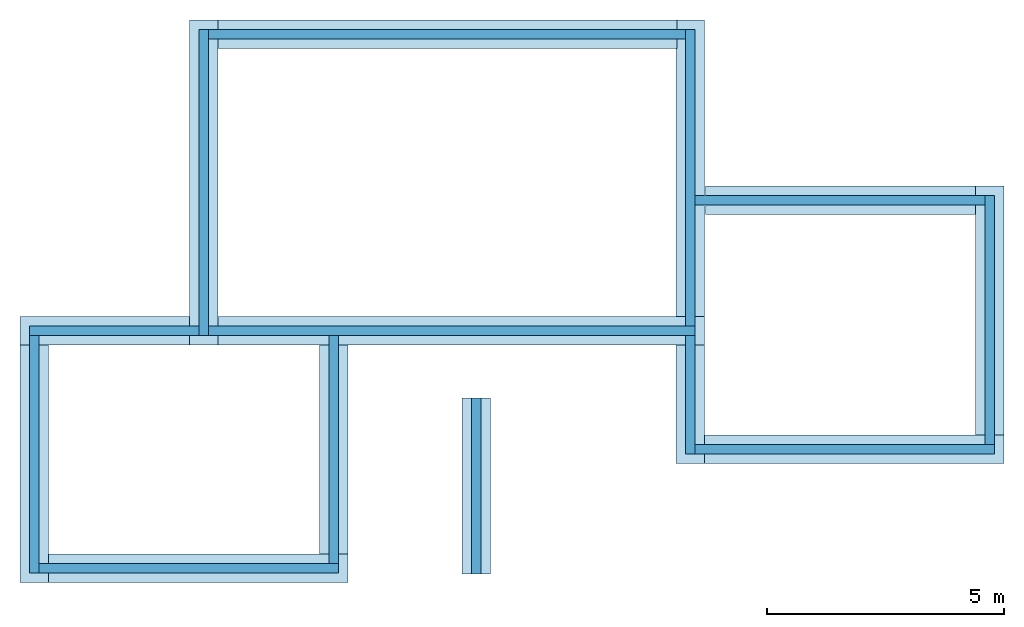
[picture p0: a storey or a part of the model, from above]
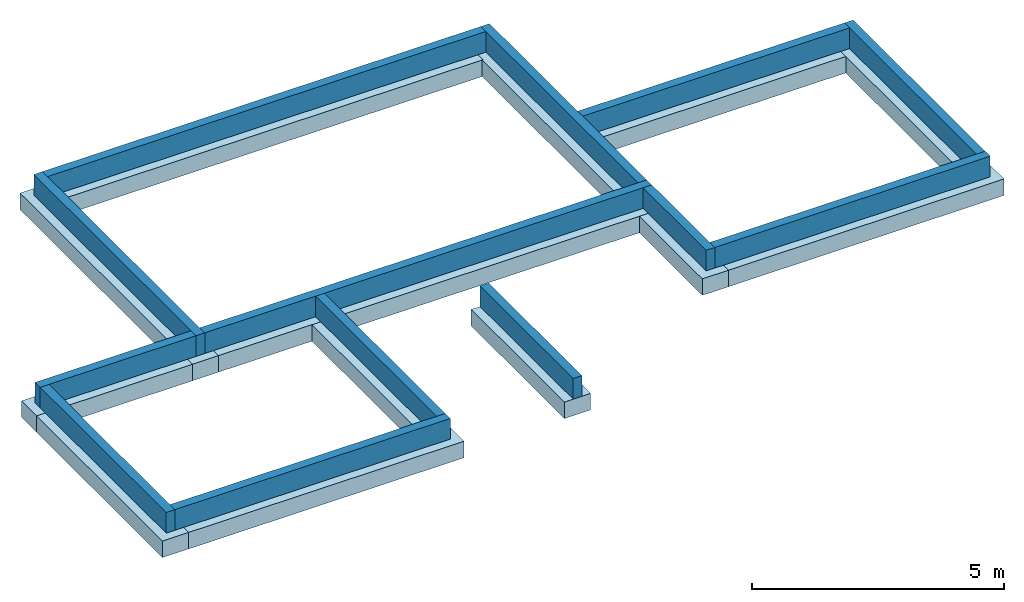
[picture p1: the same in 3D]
Properties of the parts of a building model (IFC4)

# File
Description: no view
File name: C:\Users\benjamin.carre\OneDrive - BTPCFA NOUVELLE-AQUITAINE\Bureau\Data.B²\Armoire BIM\Bim3D\Maquette B²\ALL21 EDC7.2.ifc
Time: 2022-07-11T13:41:35
Author: CARRE Benjamin
Organization: Nemetschek AG, Konrad-Zuse-Platz 1, 81829 Munich / Germany
Written by: EDMsix Version 2.0100.09 Sep 7 2016
Made in: Allplan 2021.1 08.04.2021 - 15:31:04

# IfcBuildingStorey (5)
In: Projet de Construction
Name | Elevation (m)
Environnement | -1.15
Fondations | -1.15
Plancher Bas | -0.25
RDC | -0.05
R+1 | 2.8

# IfcSpace (14)
AllplanAttributes - Pourtour de la salle: R; Type_surface_277: N; Type_surface_surf_habitable: WO; Règl_constr_ajout_SB: 0; Type_d'utilisation_Din277: SU; Règl_constr_ajout_SHOE: 0; Pièce_ss_escalier_(Surf_hab_2m_min.): 0; Facteur_surf_habitable_pièce: 1; Facteur_DIN277: 1; Unité: m²; Nom_de_macro: Pièce
Name | In | Id_élt_Allmétré
Cellier | RDC | 0062Pce0000000003
Buanderie | RDC | 0062Pce0000000010
Cuisine | RDC | 0062Pce0000000017
Salle à Manger | RDC | 0062Pce0000000024
Salon | RDC | 0062Pce0000000031
WC | RDC | 0062Pce0000000038
Bureau | RDC | 0062Pce0000000045
Salle de Jeux | RDC | 0062Pce0000000052
Sas | RDC | 0062Pce0000000059
CH1 | R+1 | 0058Pce0000000003
Petit Salon | R+1 | 0058Pce0000000031
SDB | R+1 | 0058Pce0000000024
CH2 | R+1 | 0058Pce0000000010
CH3 | R+1 | 0058Pce0000000017

# IfcBeam (7)
In: R+1
AllplanAttributes - Métier: Charpenterie, ouvrages en bois; Unité: m³; Nom_de_macro: Sous-poutre
Pset_BeamCommon - Status: Nouvelle construction
Name | Id_élt_Allmétré
 | 0055S-p0000000019
 | 0055S-p0000000100
 | 0055S-p0000000111
 | 0055S-p0000000130
 | 0055S-p0000000137
 | 0055S-p0000000052
 | 0055S-p0000000096

# IfcBuildingElementProxy (5)
In: Environnement
AllplanAttributes - BI: 3000; BS: 0; V6: 0; V7: 0; V8: 0; V9: 0; Unité: Qt; Nom_de_macro: Macro
Name | Désignation | Id_élt_Allmétré
Banc | Banc | 0012MaU0000000058
Parasol rond | Parasol rond | 0012MaU0000000054
Parasol rond | Parasol rond | 0012MaU0000000061
Femme debout 2, blanche | Femme debout 2, blanche | 0012MaU0000000049
Banc | Banc | 0012MaU0000000069

# IfcChimney (3)
PredefinedType: USERDEFINED
AllplanAttributes - Rayon_tirage: 200; Unité: m; Nom_de_macro: Cheminée
Pset_ChimneyCommon - Status: Nouvelle construction
Name | In | Id_élt_Allmétré
 | RDC | 0045Che0000000002
 | RDC | 0045Che0000000007
 | R+1 | 0056Che0000000002

# IfcColumn (4)
In: RDC
PredefinedType: COLUMN
AllplanAttributes - Unité: m; Nom_de_macro: Poteau
Pset_ColumnCommon - Status: Nouvelle construction
Name | Id_élt_Allmétré
 | 0046Pot0000000415
 | 0046Pot0000000422
 | 0046Pot0000000423
 | 0046Pot0000000424

# IfcDoor: 1 vantail blanc 1 partie latéral
In: RDC
Type - PredefinedType: DOOR; ParameterTakesPrecedence: no
OverallHeight: 2.15 m; OverallWidth: 1.3 m
AllplanAttributes (1 vantail blanc 1 partie latéral) - V6: 0; V7: 0; V8: 0; V9: 0; Version: 3.0; Désignation: 1 vantail blanc 1 partie latérale; Plugin_désignation: MainObject; Plugin_nom_objet: SmartPartCompressed; Prendre en compte la part de vitrage: 0; Version_SMT: 6.0; Id_élt_Allmétré: 0040MaU0000002760; Unité: Qt; Nom_de_macro: Macro de porte, SmartPart
AllplanQuantities - GlassSurface: 0.5025; HeightWindowSillOutside: 0; HeightWindowSillInside: 0; OffsetOpeningBottom: 0; OffsetOpeningTop: 0; OffsetOpeningLeft: 0; OffsetOpeningRight: 0; DeductionOpeningBottom: 0; DeductionOpeningLeft: 70; DeductionOpeningRight: 70; DeductionOpeningTop: 70

# IfcDoor: 1 vantail encadrement, blanc
In: RDC
Type - PredefinedType: DOOR; OperationType: SINGLE_SWING_RIGHT; ParameterTakesPrecedence: no
Type - IfcDoorLiningProperties - LiningDepth: 0.07 m; LiningThickness: 0.07 m; LiningOffset: 0 m; LiningToPanelOffsetX: 0 m; LiningToPanelOffsetY: 0 m
OverallHeight: 2.15 m; OverallWidth: 0.9 m
AllplanAttributes (1 vantail encadrement, blanc) - V6: 0; V7: 0; V8: 0; V9: 0; Version: 3.0; Désignation: 1 vantail encadrement, blanc; Plugin_désignation: MainObject; Plugin_nom_objet: SmartPartCompressed; Prendre en compte la part de vitrage: 0; Version_SMT: 6.0; Id_élt_Allmétré: 0040MaU0000002792; Unité: Qt; Nom_de_macro: Macro de porte, SmartPart
AllplanQuantities - GlassSurface: 0; HeightWindowSillOutside: 0; HeightWindowSillInside: 0; OffsetOpeningBottom: 0; OffsetOpeningTop: 0; OffsetOpeningLeft: 0; OffsetOpeningRight: 0; DeductionOpeningBottom: 0; DeductionOpeningLeft: 70; DeductionOpeningRight: 70; DeductionOpeningTop: 70

# IfcDoor: 1 vantail sol fini, en bois (11)
Type - PredefinedType: DOOR; OperationType: SINGLE_SWING_RIGHT; ParameterTakesPrecedence: no
Type - IfcDoorLiningProperties - LiningDepth: 0.07 m; LiningThickness: 0.07 m; LiningOffset: 0 m; LiningToPanelOffsetX: 0 m; LiningToPanelOffsetY: 0 m
OverallHeight: 2.04 m; OverallWidth: 0.83 m
AllplanAttributes (1 vantail sol fini, en bois) - V6: 0; V7: 0; V8: 0; V9: 0; Version: 3.0; Désignation: 1 vantail sol fini, en bois; Plugin_désignation: MainObject; Plugin_nom_objet: SmartPartCompressed; Prendre en compte la part de vitrage: 0; Version_SMT: 6.0; Unité: Qt; Nom_de_macro: Macro de porte, SmartPart
AllplanQuantities - GlassSurface: 0; HeightWindowSillOutside: 0; HeightWindowSillInside: 0; OffsetOpeningBottom: 0; OffsetOpeningTop: 0; OffsetOpeningLeft: 0; OffsetOpeningRight: 0; DeductionOpeningBottom: 0; DeductionOpeningLeft: 70; DeductionOpeningRight: 70; DeductionOpeningTop: 70
Name | In | Id_élt_Allmétré
1 vantail sol fini, en bois | RDC | 0042MaU0000000401
1 vantail sol fini, en bois | RDC | 0042MaU0000000398
1 vantail sol fini, en bois | RDC | 0042MaU0000000395
1 vantail sol fini, en bois | RDC | 0042MaU0000000430
1 vantail sol fini, en bois | RDC | 0042MaU0000000433
1 vantail sol fini, en bois | RDC | 0042MaU0000000462
1 vantail sol fini, en bois | RDC | 0042MaU0000000196
1 vantail sol fini, en bois | R+1 | 0052MaU0000000496
1 vantail sol fini, en bois | R+1 | 0052MaU0000000795
1 vantail sol fini, en bois | R+1 | 0052MaU0000000901
1 vantail sol fini, en bois | R+1 | 0052MaU0000000861

# IfcDoor: 3 vantaux blanc, monté (5)
Type - PredefinedType: DOOR; ParameterTakesPrecedence: no
OverallHeight: 2.15 m; OverallWidth: 1.4 m
AllplanAttributes (3 vantaux blanc, monté) - V6: 0; V7: 0; V8: 0; V9: 0; Version: 3.0; Désignation: 3 vantaux blanc, monté; Plugin_désignation: MainObject; Plugin_nom_objet: SmartPartCompressed; Prendre en compte la part de vitrage: 100; Version_SMT: 6.0; Unité: Qt
AllplanQuantities - GlassSurface: 2.14305; HeightWindowSillOutside: 0.03; HeightWindowSillInside: 0.03; OffsetOpeningBottom: 0; OffsetOpeningTop: 0; OffsetOpeningLeft: 0; OffsetOpeningRight: 0; DeductionOpeningBottom: 70; DeductionOpeningLeft: 70; DeductionOpeningRight: 70; DeductionOpeningTop: 70
Name | In | Nom_de_macro | Id_élt_Allmétré
3 vantaux blanc, monté | RDC | Macro de fenêtre, SmartPart | 0040MaU0000003242
3 vantaux blanc, monté | RDC | Macro de fenêtre, SmartPart | 0040MaU0000003331
3 vantaux blanc, monté | RDC | Macro de fenêtre, SmartPart | 0040MaU0000003328
3 vantaux blanc, monté | R+1 | Macro de porte, SmartPart | 0050MaU0000000898
3 vantaux blanc, monté | R+1 | Macro de porte, SmartPart | 0050MaU0000000895

# IfcDoor: 3 vantaux volet roulant, blanc
In: RDC
Type - PredefinedType: DOOR; ParameterTakesPrecedence: no
OverallHeight: 2.15 m; OverallWidth: 2.4 m
AllplanAttributes (3 vantaux volet roulant, blanc) - V6: 0; V7: 0; V8: 0; V9: 0; Version: 3.0; Désignation: 3 vantaux volet roulant, blanc; Plugin_désignation: MainObject; Plugin_nom_objet: SmartPartCompressed; Prendre en compte la part de vitrage: 100; Version_SMT: 6.0; Id_élt_Allmétré: 0040MaU0000003632; Unité: Qt; Nom_de_macro: Macro de porte, SmartPart
AllplanQuantities - GlassSurface: 3.70073; HeightWindowSillOutside: 0.03; HeightWindowSillInside: 0.03; OffsetOpeningBottom: 0; OffsetOpeningTop: 0; OffsetOpeningLeft: 0; OffsetOpeningRight: 0; DeductionOpeningBottom: 70; DeductionOpeningLeft: 70; DeductionOpeningRight: 70; DeductionOpeningTop: 150

# IfcFooting (13)
In: Fondations
PredefinedType: STRIP_FOOTING
AllplanAttributes - Métier: Maçonnerie; Unité: m³; Nom_de_macro: Semelle filante
Pset_FootingCommon - Status: Nouvelle construction
Name | Id_élt_Allmétré
 | 0020SeF0000000046
 | 0020SeF0000000067
 | 0020SeF0000000055
 | 0020SeF0000000129
 | 0020SeF0000000117
 | 0020SeF0000000105
 | 0020SeF0000000028
 | 0020SeF0000000006
 | 0020SeF0000000016
 | 0020SeF0000000096
 | 0020SeF0000000079
 | 0020SeF0000000002
 | 0020SeF0000000179

# IfcFurniture (32)
AllplanAttributes - V6: 0; V7: 0; V8: 0; V9: 0; Nom_de_macro: Meubles
Name | In | BI | BS | Unité | Désignation | Id_élt_Allmétré
Fauteuil C | Environnement | 3100 | 0 | Pcs | Fauteuil C | 0011Meu0000000032
Sofa G | Environnement | 0 | 0 | Pcs | Sofa G | 0011Meu0000000038
Table basse A 100x50x42 | Environnement | 0 | 0 | Pcs | Table basse A 100x50x42 | 0011Meu0000000044
TV 48 pouces | Environnement | 0 | 0 | Qt | TV 48 pouces | 0011Meu0000000049
Fauteuil I | Environnement | 0 | 0 | Pcs | Fauteuil I | 0011Meu0000000056
Table C 180x90x75 | Environnement | 0 | 0 | Pcs | Table C 180x90x75 | 0011Meu0000000061
Chaise G | Environnement | 0 | 0 | Pcs | Chaise G | 0011Meu0000000070
Chaise G | Environnement | 0 | 0 | Pcs | Chaise G | 0011Meu0000000075
Chaise G | Environnement | 0 | 0 | Pcs | Chaise G | 0011Meu0000000077
Chaise G | Environnement | 0 | 0 | Pcs | Chaise G | 0011Meu0000000079
Elément 4 | Environnement | 0 | 0 | Pcs | Elément 4 | 0011Meu0000000097
Elément 7 évier | Environnement | 0 | 0 | Pcs | Elément 7 évier | 0011Meu0000000089
Elément 8 | Environnement | 0 | 0 | Qt | Elément 8 | 0011Meu0000000109
Elément 5 cuisinière | Environnement | 0 | 0 | Pcs | Elément 5 cuisinière | 0011Meu0000000115
Elément 8 | Environnement | 0 | 0 | Qt | Elément 8 | 0011Meu0000000128
Elément 2 four | Environnement | 0 | 0 | Qt | Elément 2 four | 0011Meu0000000122
Table B 130x70 | Environnement | 0 | 0 | Pcs | Table B 130x70 | 0011Meu0000000148
Chaise de bureau E | Environnement | 0 | 0 | Qt | Chaise de bureau E | 0011Meu0000000152
Etagère B 214x46x100 | Environnement | 0 | 0 | Qt | Etagère B 214x46x100 | 0011Meu0000000158
Sofa G | Environnement | 0 | 0 | Pcs | Sofa G | 0011Meu0000000173
TV 48 pouces | Environnement | 0 | 0 | Qt | TV 48 pouces | 0011Meu0000000175
Lit A 90x200 | Environnement | 3100 | 0 | Pcs | Lit A 90x200 | 0012Meu0000000002
Table de nuit A | Environnement | 3100 | 0 | Pcs | Table de nuit A | 0012Meu0000000010
Lit A 90x200 | Environnement | 3100 | 0 | Pcs | Lit A 90x200 | 0012Meu0000000015
Table de nuit A | Environnement | 3100 | 0 | Pcs | Table de nuit A | 0012Meu0000000021
Lit B 140x200 | Environnement | 3100 | 0 | Pcs | Lit B 140x200 | 0012Meu0000000028
Table de nuit A | Environnement | 3100 | 0 | Pcs | Table de nuit A | 0012Meu0000000029
Table de nuit A | Environnement | 3100 | 0 | Pcs | Table de nuit A | 0012Meu0000000039
WC, debout, avec réservoir | RDC | 0 | 50 | Qt | WC, debout, avec réservoir | 0060Meu0000000003
Lavabo 36,5 | RDC | 800 | 0 | Qt | Lavabo 36,5 | 0060Meu0000000012
Douche 100 x 100 | R+1 | 3100 | 0 | Qt | Douche 100 x 100 | 0057Meu0000000004
Lavabo double 120 | R+1 | 3900 | 999199999200000 | Qt | Lavabo double 120 | 0057Meu0000000010

# IfcOpeningStandardCase (40)
PredefinedType: OPENING
AllplanAttributes - Object Layer Attributes #1, Unité: m²
Pset_OpeningElementCommon - Status: Nouvelle construction
Name | In | Object Layer Attributes #1, Métier | Object Layer Attributes #1, Mode_d'ouverture_porte | Object Layer Attributes #1, Id_élt_Allmétré | Object Layer Attributes #1, Nom_de_macro | Object Layer Attributes #2, Catégorie de transformation = Object Layer Attributes #3, Catégorie de transformation | Object Layer Attributes #2, Métier | Object Layer Attributes #2, Id_élt_Allmétré | Object Layer Attributes #2, Unité = Object Layer Attributes #3, Unité | Object Layer Attributes #2, Nom_de_macro = Object Layer Attributes #3, Nom_de_macro | Object Layer Attributes #3, Métier | Object Layer Attributes #3, Id_élt_Allmétré
Baie de porte | RDC | Systèmes d'isolation thermique | - | 0040Por0000002178 | Baie de porte | Nouvelle construction | Maçonnerie | 0040Por0000002177 | m² | Baie de porte | Peintures | 0040Por0000002176 | AllplanAttributes - Object Layer Attributes #2, Mode_d'ouverture_porte: -; Object Layer Attributes #3, Mode_d'ouverture_porte: -
Baie de fenêtre | RDC | Systèmes d'isolation thermique |  | 0040Fen0000002530 | Baie de fenêtre | Nouvelle construction | Maçonnerie | 0040Fen0000002529 | m² | Baie de fenêtre | Peintures | 0040Fen0000002528
Baie de fenêtre | RDC | Systèmes d'isolation thermique |  | 0040Fen0000002684 | Baie de fenêtre | Nouvelle construction | Maçonnerie | 0040Fen0000002683 | m² | Baie de fenêtre | Peintures | 0040Fen0000002682
Baie de fenêtre | RDC | Systèmes d'isolation thermique |  | 0040Fen0000002664 | Baie de fenêtre | Nouvelle construction | Maçonnerie | 0040Fen0000002663 | m² | Baie de fenêtre | Peintures | 0040Fen0000002662
Baie de fenêtre | RDC | Systèmes d'isolation thermique |  | 0040Fen0000002704 | Baie de fenêtre | Nouvelle construction | Maçonnerie | 0040Fen0000002703 | m² | Baie de fenêtre | Peintures | 0040Fen0000002702
Baie de fenêtre | RDC | Systèmes d'isolation thermique |  | 0040Fen0000002644 | Baie de fenêtre | Nouvelle construction | Maçonnerie | 0040Fen0000002643 | m² | Baie de fenêtre | Peintures | 0040Fen0000002642
Baie de porte | RDC | Systèmes d'isolation thermique | - | 0040Por0000002152 | Baie de porte | Nouvelle construction | Maçonnerie | 0040Por0000002151 | m² | Baie de porte | Peintures | 0040Por0000002150 | AllplanAttributes - Object Layer Attributes #2, Mode_d'ouverture_porte: -; Object Layer Attributes #3, Mode_d'ouverture_porte: -
Baie de porte | RDC | Systèmes d'isolation thermique | DIN R | 0040Por0000002384 | Baie de porte | Nouvelle construction | Maçonnerie | 0040Por0000002383 | m² | Baie de porte | Peintures | 0040Por0000002382 | AllplanAttributes - Object Layer Attributes #2, Mode_d'ouverture_porte: DIN R; Object Layer Attributes #3, Mode_d'ouverture_porte: DIN R
Baie de porte | RDC | Systèmes d'isolation thermique | - | 0040Por0000002080 | Baie de porte | Nouvelle construction | Maçonnerie | 0040Por0000002081 | m² | Baie de porte | Peintures | 0040Por0000002082 | AllplanAttributes - Object Layer Attributes #2, Mode_d'ouverture_porte: -; Object Layer Attributes #3, Mode_d'ouverture_porte: -
Baie de porte | RDC | Systèmes d'isolation thermique | - | 0040Por0000002110 | Baie de porte | Nouvelle construction | Maçonnerie | 0040Por0000002111 | m² | Baie de porte | Peintures | 0040Por0000002112 | AllplanAttributes - Object Layer Attributes #2, Mode_d'ouverture_porte: -; Object Layer Attributes #3, Mode_d'ouverture_porte: -
Baie de porte | RDC | Systèmes d'isolation thermique | DIN L | 0040Por0000002198 | Baie de porte | Nouvelle construction | Maçonnerie | 0040Por0000002197 | m² | Baie de porte | Peintures | 0040Por0000002196 | AllplanAttributes - Object Layer Attributes #2, Mode_d'ouverture_porte: DIN L; Object Layer Attributes #3, Mode_d'ouverture_porte: DIN L
Baie de porte | RDC | Systèmes d'isolation thermique | - | 0040Por0000002218 | Baie de porte | Nouvelle construction | Maçonnerie | 0040Por0000002217 | m² | Baie de porte | Peintures | 0040Por0000002216 | AllplanAttributes - Object Layer Attributes #2, Mode_d'ouverture_porte: -; Object Layer Attributes #3, Mode_d'ouverture_porte: -
Baie de fenêtre | RDC | Systèmes d'isolation thermique |  | 0040Fen0000002550 | Baie de fenêtre | Nouvelle construction | Maçonnerie | 0040Fen0000002549 | m² | Baie de fenêtre | Peintures | 0040Fen0000002548
Baie de fenêtre | RDC | Systèmes d'isolation thermique |  | 0040Fen0000002404 | Baie de fenêtre | Nouvelle construction | Maçonnerie | 0040Fen0000002403 | m² | Baie de fenêtre | Peintures | 0040Fen0000002402
Baie de porte | RDC | Systèmes d'isolation thermique | DIN L | 0040Por0000002264 | Baie de porte | Nouvelle construction | Maçonnerie | 0040Por0000002263 | m² | Baie de porte | Peintures | 0040Por0000002262 | AllplanAttributes - Object Layer Attributes #2, Mode_d'ouverture_porte: DIN L; Object Layer Attributes #3, Mode_d'ouverture_porte: DIN L
Baie de fenêtre | RDC | Systèmes d'isolation thermique |  | 0040Fen0000002624 | Baie de fenêtre | Nouvelle construction | Maçonnerie | 0040Fen0000002623 | m² | Baie de fenêtre | Peintures | 0040Fen0000002622
Baie de porte | RDC | Peintures | - | 0041Por0000000034 | Baie de porte | Nouvelle construction | Maçonnerie | 0041Por0000000035 | m² | Baie de porte | Peintures | 0041Por0000000036 | AllplanAttributes - Object Layer Attributes #2, Mode_d'ouverture_porte: -; Object Layer Attributes #3, Mode_d'ouverture_porte: -
Baie de porte | RDC | Peintures | DIN R | 0042Por0000000128 | Baie de porte
Baie de porte | RDC | Peintures | DIN L | 0042Por0000000118 | Baie de porte
Baie de porte | RDC | Peintures | DIN R | 0042Por0000000098 | Baie de porte
Baie de porte | RDC | Peintures | DIN L | 0042Por0000000148 | Baie de porte
Baie de porte | RDC | Peintures | DIN R | 0042Por0000000138 | Baie de porte
Baie de porte | RDC | Peintures | DIN R | 0042Por0000000158 | Baie de porte
Baie de porte | RDC | Peintures | DIN L | 0042Por0000000088 | Baie de porte
Trémie dans dalle | RDC | Enduits et plâtrages |  | 0044TrD0000000016 | Trémie
Trémie dans dalle | RDC | Enduits et plâtrages |  | 0044TrD0000000011 | Trémie
Trémie dans dalle | RDC | Maçonnerie |  | 0047TrD0000000279 | Trémie
Baie de fenêtre | R+1 | Systèmes d'isolation thermique |  | 0050Fen0000000597 | Baie de fenêtre | Nouvelle construction | Maçonnerie | 0050Fen0000000596 | m² | Baie de fenêtre | Peintures | 0050Fen0000000595
Baie de porte | R+1 | Systèmes d'isolation thermique | - | 0050Por0000000551 | Baie de porte | Nouvelle construction | Maçonnerie | 0050Por0000000550 | m² | Baie de porte | Peintures | 0050Por0000000549 | AllplanAttributes - Object Layer Attributes #2, Mode_d'ouverture_porte: -; Object Layer Attributes #3, Mode_d'ouverture_porte: -
Baie de fenêtre | R+1 | Systèmes d'isolation thermique |  | 0050Fen0000000617 | Baie de fenêtre | Nouvelle construction | Maçonnerie | 0050Fen0000000616 | m² | Baie de fenêtre | Peintures | 0050Fen0000000615
Baie de fenêtre | R+1 | Systèmes d'isolation thermique |  | 0050Fen0000001254 | Baie de fenêtre | Nouvelle construction | Maçonnerie | 0050Fen0000001253 | m² | Baie de fenêtre | Peintures | 0050Fen0000001252
Baie de porte | R+1 | Systèmes d'isolation thermique | - | 0050Por0000000479 | Baie de porte | Nouvelle construction | Maçonnerie | 0050Por0000000478 | m² | Baie de porte | Peintures | 0050Por0000000477 | AllplanAttributes - Object Layer Attributes #2, Mode_d'ouverture_porte: -; Object Layer Attributes #3, Mode_d'ouverture_porte: -
Baie de porte | R+1 | Systèmes d'isolation thermique | - | 0050Por0000001361 | Baie de porte
Baie de porte | R+1 | Systèmes d'isolation thermique | - | 0050Por0000001389 | Baie de porte
Trémie dans dalle | R+1 | Maçonnerie |  | 0051TrD0000000005 | Trémie
Trémie dans dalle | R+1 | Maçonnerie |  | 0051TrD0000000010 | Trémie
Baie de porte | R+1 | Enduits et plâtrages | DIN R | 0052Por0000000458 | Baie de porte
Baie de porte | R+1 | Enduits et plâtrages | DIN R | 0052Por0000000757 | Baie de porte
Baie de porte | R+1 | Enduits et plâtrages | DIN R | 0052Por0000000863 | Baie de porte
Baie de porte | R+1 | Enduits et plâtrages | DIN L | 0052Por0000000823 | Baie de porte

# IfcRoof
In: R+1
AllplanAttributes - Object Layer Attributes #1, Métier: Couverture; Object Layer Attributes #1, Id_élt_Allmétré: 0055Ctt0000000002; Object Layer Attributes #1, Unité: m²; Object Layer Attributes #1, Nom_de_macro: Couverture poly; Object Layer Attributes #2, Catégorie de transformation: Nouvelle construction; Object Layer Attributes #2, Métier: Charpenterie, ouvrages en bois; Object Layer Attributes #2, Id_élt_Allmétré: 0055Ctt0000000003; Object Layer Attributes #2, Unité: m²; Object Layer Attributes #2, Nom_de_macro: Couverture poly
Pset_RoofCommon - Status: Nouvelle construction

# IfcSlab (34)
Name | In | PredefinedType | Métier | Id_élt_Allmétré | Unité | Nom_de_macro | Status
 | Environnement | FLOOR | Aménagement paysager | 0010Dal0000000004 | m² | Dalle | Nouvelle construction
 | Plancher Bas | FLOOR | Maçonnerie | 0030Dal0000000005 | m² | Dalle | Nouvelle construction | Material: Plancher Hourdis type KP1; AllplanAttributes - Matériau: Plancher Hourdis type KP1
 | Plancher Bas | FLOOR | Maçonnerie | 0030Dal0000000002 | m² | Dalle | Nouvelle construction | Material: Plancher Hourdis type KP1; AllplanAttributes - Matériau: Plancher Hourdis type KP1
 | Plancher Bas | FLOOR | Maçonnerie | 0030Dal0000000010 | m² | Dalle | Nouvelle construction | Material: Plancher Hourdis type KP1; AllplanAttributes - Matériau: Plancher Hourdis type KP1
 | Plancher Bas | FLOOR | Maçonnerie | 0031Dal0000000007 | m² | Dalle | Nouvelle construction
 | Plancher Bas | FLOOR | Maçonnerie | 0031Dal0000000012 | m² | Dalle | Nouvelle construction
 | Plancher Bas | FLOOR | Maçonnerie | 0031Dal0000000017 | m² | Dalle | Nouvelle construction
 | Plancher Bas | FLOOR | Maçonnerie | 0031Dal0000000022 | m² | Dalle | Nouvelle construction
 | Plancher Bas | FLOOR | Maçonnerie | 0031Dal0000000027 | m² | Dalle | Nouvelle construction
 | Plancher Bas | FLOOR | Maçonnerie | 0031Dal0000000037 | m² | Dalle | Nouvelle construction
 | Plancher Bas | FLOOR | Maçonnerie | 0031Dal0000000032 | m² | Dalle | Nouvelle construction
 | Plancher Bas | FLOOR | Maçonnerie | 0031Dal0000000002 | m² | Dalle | Nouvelle construction
 | RDC | FLOOR | Enduits et plâtrages | 0044Dal0000000008 | m² | Plafond | Nouvelle construction
 | RDC | FLOOR | Enduits et plâtrages | 0044Dal0000000002 | m² | Plafond | Nouvelle construction
 | RDC | FLOOR | Enduits et plâtrages | 0044Dal0000000005 | m² | Plafond | Nouvelle construction
 | RDC | FLOOR | Maçonnerie | 0046Dal0000000274 | m² | Dalle | Nouvelle construction
 | RDC | FLOOR | Maçonnerie | 0047Dal0000000045 | m² | Dalle | Nouvelle construction
 | RDC | FLOOR | Maçonnerie | 0047Dal0000000038 | m² | Dalle | Nouvelle construction
 | RDC | FLOOR | Maçonnerie | 0047Dal0000000144 | m² | Dalle | Nouvelle construction
 | RDC | FLOOR | Maçonnerie | 0047Dal0000000033 | m² | Dalle | Nouvelle construction
 | RDC | FLOOR | Maçonnerie | 0047Dal0000000077 | m² | Dalle | Nouvelle construction
 | RDC | FLOOR | Maçonnerie | 0047Dal0000000003 | m² | Dalle | Nouvelle construction
 | RDC | FLOOR | Maçonnerie | 0047Dal0000000052 | m² | Dalle | Nouvelle construction
 | RDC | FLOOR | Maçonnerie | 0047Dal0000000011 | m² | Dalle | Nouvelle construction
 | RDC | FLOOR | Maçonnerie | 0047Dal0000000268 | m² | Dalle | Nouvelle construction
 | RDC | FLOOR | Carrelage et dallage | 0061Dal0000000011 | m² | Dalle | Nouvelle construction
 | RDC | FLOOR | Carrelage et dallage | 0061Dal0000000008 | m² | Dalle | Nouvelle construction
 | RDC | FLOOR | Carrelage et dallage | 0061Dal0000000018 | m² | Dalle | Nouvelle construction
 | RDC | FLOOR | Carrelage et dallage | 0061Dal0000000005 | m² | Dalle | Nouvelle construction
 | RDC | FLOOR | Carrelage et dallage | 0061Dal0000000002 | m² | Dalle | Nouvelle construction
 | R+1 | FLOOR | Maçonnerie | 0051Dal0000000002 | m² | Dalle | Nouvelle construction
 | R+1 | FLOOR | Systèmes d'isolation thermique | 0054Dal0000000002 | m² | Plafond | Nouvelle construction
2 x  | R+1 | ROOF

# IfcStair
In: RDC
Material: Escalier à un quartier tournant
AllplanAttributes - Matériau: Escalier à un quartier tournant; Id_élt_Allmétré: 0049Esc0000000244; Unité: Qt; Nom_de_macro: Escalier
Pset_StairCommon - NumberOfRiser: 19; RiserHeight: 163.158 m; TreadLength: 281.337 m; NumberOfTreads: 19

# IfcWall (69)
AllplanAttributes - Unité: m³; Nom_de_macro: Mur entier; Object Layer Attributes #1, Catégorie de transformation: Nouvelle construction; Object Layer Attributes #1, Unité: m²; Object Layer Attributes #1, Nom_de_macro: Mur
Name | In | Material | Id_élt_Allmétré | Object Layer Attributes #1, Métier | Object Layer Attributes #1, Id_élt_Allmétré
 | Fondations | layer 0.2 m | 0021HMu0000000020 | Maçonnerie | 0021Mu_0000000021
 | Fondations | layer 0.2 m | 0021HMu0000000025 | Maçonnerie | 0021Mu_0000000026
 | Fondations | layer 0.2 m | 0021HMu0000000036 | Maçonnerie | 0021Mu_0000000037
 | Fondations | layer 0.2 m | 0021HMu0000000047 | Maçonnerie | 0021Mu_0000000048
 | Fondations | layer 0.2 m | 0021HMu0000000064 | Maçonnerie | 0021Mu_0000000065
 | Fondations | layer 0.2 m | 0021HMu0000000074 | Maçonnerie | 0021Mu_0000000075
 | Fondations | layer 0.2 m | 0021HMu0000000085 | Maçonnerie | 0021Mu_0000000086
 | Fondations | layer 0.2 m | 0021HMu0000000096 | Maçonnerie | 0021Mu_0000000097
 | Fondations | layer 0.2 m | 0021HMu0000000112 | Maçonnerie | 0021Mu_0000000113
 | Fondations | layer 0.2 m | 0021HMu0000000122 | Maçonnerie | 0021Mu_0000000123
 | Fondations | layer 0.2 m | 0021HMu0000000133 | Maçonnerie | 0021Mu_0000000134
 | Fondations | layer 0.2 m | 0021HMu0000000144 | Maçonnerie | 0021Mu_0000000145
 | Fondations | layer 0.2 m | 0021HMu0000000160 | Maçonnerie | 0021Mu_0000000161
 | RDC | layer 0.2 m, layer 0.2 m, layer 0.02 m | 0040HMu0000000238 | Systèmes d'isolation thermique | 0040Mu_0000000239 | AllplanAttributes - Object Layer Attributes #2, Catégorie de transformation: Nouvelle construction; Object Layer Attributes #2, Métier: Maçonnerie; Object Layer Attributes #2, Id_élt_Allmétré: 0040Mu_0000000240; Object Layer Attributes #2, Unité: m²; Object Layer Attributes #2, Nom_de_macro: Mur; Object Layer Attributes #3, Catégorie de transformation: Nouvelle construction; Object Layer Attributes #3, Métier: Peintures; Object Layer Attributes #3, Id_élt_Allmétré: 0040Mu_0000000241; Object Layer Attributes #3, Unité: m²; Object Layer Attributes #3, Nom_de_macro: Mur
 | RDC | layer 0.2 m, layer 0.2 m, layer 0.02 m | 0040HMu0000000279 | Systèmes d'isolation thermique | 0040Mu_0000000280 | AllplanAttributes - Object Layer Attributes #2, Catégorie de transformation: Nouvelle construction; Object Layer Attributes #2, Métier: Maçonnerie; Object Layer Attributes #2, Id_élt_Allmétré: 0040Mu_0000000281; Object Layer Attributes #2, Unité: m²; Object Layer Attributes #2, Nom_de_macro: Mur; Object Layer Attributes #3, Catégorie de transformation: Nouvelle construction; Object Layer Attributes #3, Métier: Peintures; Object Layer Attributes #3, Id_élt_Allmétré: 0040Mu_0000000282; Object Layer Attributes #3, Unité: m²; Object Layer Attributes #3, Nom_de_macro: Mur
 | RDC | layer 0.2 m, layer 0.2 m, layer 0.02 m | 0040HMu0000000320 | Systèmes d'isolation thermique | 0040Mu_0000000321 | AllplanAttributes - Object Layer Attributes #2, Catégorie de transformation: Nouvelle construction; Object Layer Attributes #2, Métier: Maçonnerie; Object Layer Attributes #2, Id_élt_Allmétré: 0040Mu_0000000322; Object Layer Attributes #2, Unité: m²; Object Layer Attributes #2, Nom_de_macro: Mur; Object Layer Attributes #3, Catégorie de transformation: Nouvelle construction; Object Layer Attributes #3, Métier: Peintures; Object Layer Attributes #3, Id_élt_Allmétré: 0040Mu_0000000323; Object Layer Attributes #3, Unité: m²; Object Layer Attributes #3, Nom_de_macro: Mur
 | RDC | layer 0.2 m, layer 0.2 m, layer 0.02 m | 0040HMu0000000359 | Systèmes d'isolation thermique | 0040Mu_0000000360 | AllplanAttributes - Object Layer Attributes #2, Catégorie de transformation: Nouvelle construction; Object Layer Attributes #2, Métier: Maçonnerie; Object Layer Attributes #2, Id_élt_Allmétré: 0040Mu_0000000361; Object Layer Attributes #2, Unité: m²; Object Layer Attributes #2, Nom_de_macro: Mur; Object Layer Attributes #3, Catégorie de transformation: Nouvelle construction; Object Layer Attributes #3, Métier: Peintures; Object Layer Attributes #3, Id_élt_Allmétré: 0040Mu_0000000362; Object Layer Attributes #3, Unité: m²; Object Layer Attributes #3, Nom_de_macro: Mur
 | RDC | layer 0.2 m, layer 0.2 m, layer 0.02 m | 0040HMu0000001010 | Systèmes d'isolation thermique | 0040Mu_0000001011 | AllplanAttributes - Object Layer Attributes #2, Catégorie de transformation: Nouvelle construction; Object Layer Attributes #2, Métier: Maçonnerie; Object Layer Attributes #2, Id_élt_Allmétré: 0040Mu_0000001012; Object Layer Attributes #2, Unité: m²; Object Layer Attributes #2, Nom_de_macro: Mur; Object Layer Attributes #3, Catégorie de transformation: Nouvelle construction; Object Layer Attributes #3, Métier: Peintures; Object Layer Attributes #3, Id_élt_Allmétré: 0040Mu_0000001013; Object Layer Attributes #3, Unité: m²; Object Layer Attributes #3, Nom_de_macro: Mur
 | RDC | layer 0.2 m, layer 0.2 m, layer 0.02 m | 0040HMu0000001040 | Systèmes d'isolation thermique | 0040Mu_0000001041 | AllplanAttributes - Object Layer Attributes #2, Catégorie de transformation: Nouvelle construction; Object Layer Attributes #2, Métier: Maçonnerie; Object Layer Attributes #2, Id_élt_Allmétré: 0040Mu_0000001042; Object Layer Attributes #2, Unité: m²; Object Layer Attributes #2, Nom_de_macro: Mur; Object Layer Attributes #3, Catégorie de transformation: Nouvelle construction; Object Layer Attributes #3, Métier: Peintures; Object Layer Attributes #3, Id_élt_Allmétré: 0040Mu_0000001043; Object Layer Attributes #3, Unité: m²; Object Layer Attributes #3, Nom_de_macro: Mur
 | RDC | layer 0.2 m, layer 0.2 m, layer 0.02 m | 0040HMu0000001079 | Systèmes d'isolation thermique | 0040Mu_0000001080 | AllplanAttributes - Object Layer Attributes #2, Catégorie de transformation: Nouvelle construction; Object Layer Attributes #2, Métier: Maçonnerie; Object Layer Attributes #2, Id_élt_Allmétré: 0040Mu_0000001081; Object Layer Attributes #2, Unité: m²; Object Layer Attributes #2, Nom_de_macro: Mur; Object Layer Attributes #3, Catégorie de transformation: Nouvelle construction; Object Layer Attributes #3, Métier: Peintures; Object Layer Attributes #3, Id_élt_Allmétré: 0040Mu_0000001082; Object Layer Attributes #3, Unité: m²; Object Layer Attributes #3, Nom_de_macro: Mur
 | RDC | layer 0.2 m, layer 0.2 m, layer 0.02 m | 0040HMu0000001118 | Systèmes d'isolation thermique | 0040Mu_0000001119 | AllplanAttributes - Object Layer Attributes #2, Catégorie de transformation: Nouvelle construction; Object Layer Attributes #2, Métier: Maçonnerie; Object Layer Attributes #2, Id_élt_Allmétré: 0040Mu_0000001120; Object Layer Attributes #2, Unité: m²; Object Layer Attributes #2, Nom_de_macro: Mur; Object Layer Attributes #3, Catégorie de transformation: Nouvelle construction; Object Layer Attributes #3, Métier: Peintures; Object Layer Attributes #3, Id_élt_Allmétré: 0040Mu_0000001121; Object Layer Attributes #3, Unité: m²; Object Layer Attributes #3, Nom_de_macro: Mur
 | RDC | layer 0.02 m, layer 0.2 m, layer 0.02 m | 0040HMu0000001483 | Systèmes d'isolation thermique | 0040Mu_0000001484 | AllplanAttributes - Object Layer Attributes #2, Catégorie de transformation: Nouvelle construction; Object Layer Attributes #2, Métier: Maçonnerie; Object Layer Attributes #2, Id_élt_Allmétré: 0040Mu_0000001485; Object Layer Attributes #2, Unité: m²; Object Layer Attributes #2, Nom_de_macro: Mur; Object Layer Attributes #3, Catégorie de transformation: Nouvelle construction; Object Layer Attributes #3, Métier: Peintures; Object Layer Attributes #3, Id_élt_Allmétré: 0040Mu_0000001486; Object Layer Attributes #3, Unité: m²; Object Layer Attributes #3, Nom_de_macro: Mur
 | RDC | layer 0.02 m, layer 0.2 m, layer 0.02 m | 0040HMu0000001342 | Systèmes d'isolation thermique | 0040Mu_0000001343 | AllplanAttributes - Object Layer Attributes #2, Catégorie de transformation: Nouvelle construction; Object Layer Attributes #2, Métier: Maçonnerie; Object Layer Attributes #2, Id_élt_Allmétré: 0040Mu_0000001344; Object Layer Attributes #2, Unité: m²; Object Layer Attributes #2, Nom_de_macro: Mur; Object Layer Attributes #3, Catégorie de transformation: Nouvelle construction; Object Layer Attributes #3, Métier: Peintures; Object Layer Attributes #3, Id_élt_Allmétré: 0040Mu_0000001345; Object Layer Attributes #3, Unité: m²; Object Layer Attributes #3, Nom_de_macro: Mur
 | RDC | layer 0.2 m, layer 0.2 m, layer 0.02 m | 0040HMu0000001157 | Systèmes d'isolation thermique | 0040Mu_0000001158 | AllplanAttributes - Object Layer Attributes #2, Catégorie de transformation: Nouvelle construction; Object Layer Attributes #2, Métier: Maçonnerie; Object Layer Attributes #2, Id_élt_Allmétré: 0040Mu_0000001159; Object Layer Attributes #2, Unité: m²; Object Layer Attributes #2, Nom_de_macro: Mur; Object Layer Attributes #3, Catégorie de transformation: Nouvelle construction; Object Layer Attributes #3, Métier: Peintures; Object Layer Attributes #3, Id_élt_Allmétré: 0040Mu_0000001160; Object Layer Attributes #3, Unité: m²; Object Layer Attributes #3, Nom_de_macro: Mur
 | RDC | layer 0.2 m, layer 0.2 m, layer 0.0199668 m | 0040HMu0000000910 | Systèmes d'isolation thermique | 0040Mu_0000000911 | AllplanAttributes - Object Layer Attributes #2, Catégorie de transformation: Nouvelle construction; Object Layer Attributes #2, Métier: Maçonnerie; Object Layer Attributes #2, Id_élt_Allmétré: 0040Mu_0000000912; Object Layer Attributes #2, Unité: m²; Object Layer Attributes #2, Nom_de_macro: Mur; Object Layer Attributes #3, Catégorie de transformation: Nouvelle construction; Object Layer Attributes #3, Métier: Peintures; Object Layer Attributes #3, Id_élt_Allmétré: 0040Mu_0000000913; Object Layer Attributes #3, Unité: m²; Object Layer Attributes #3, Nom_de_macro: Mur
 | RDC | layer 0.2 m, layer 0.2 m, layer 0.02 m | 0040HMu0000000087 | Systèmes d'isolation thermique | 0040Mu_0000000088 | AllplanAttributes - Object Layer Attributes #2, Catégorie de transformation: Nouvelle construction; Object Layer Attributes #2, Métier: Maçonnerie; Object Layer Attributes #2, Id_élt_Allmétré: 0040Mu_0000000089; Object Layer Attributes #2, Unité: m²; Object Layer Attributes #2, Nom_de_macro: Mur; Object Layer Attributes #3, Catégorie de transformation: Nouvelle construction; Object Layer Attributes #3, Métier: Peintures; Object Layer Attributes #3, Id_élt_Allmétré: 0040Mu_0000000090; Object Layer Attributes #3, Unité: m²; Object Layer Attributes #3, Nom_de_macro: Mur
 | RDC | layer 0.2 m, layer 0.2 m, layer 0.02 m | 0040HMu0000000852 | Systèmes d'isolation thermique | 0040Mu_0000000853 | AllplanAttributes - Object Layer Attributes #2, Catégorie de transformation: Nouvelle construction; Object Layer Attributes #2, Métier: Maçonnerie; Object Layer Attributes #2, Id_élt_Allmétré: 0040Mu_0000000854; Object Layer Attributes #2, Unité: m²; Object Layer Attributes #2, Nom_de_macro: Mur; Object Layer Attributes #3, Catégorie de transformation: Nouvelle construction; Object Layer Attributes #3, Métier: Peintures; Object Layer Attributes #3, Id_élt_Allmétré: 0040Mu_0000000855; Object Layer Attributes #3, Unité: m²; Object Layer Attributes #3, Nom_de_macro: Mur
 | RDC | layer 0.05 m, layer 0.2 m, layer 0.05 m | 0041HMu0000000002 | Peintures | 0041Mu_0000000003 | AllplanAttributes - Object Layer Attributes #2, Catégorie de transformation: Nouvelle construction; Object Layer Attributes #2, Métier: Maçonnerie; Object Layer Attributes #2, Id_élt_Allmétré: 0041Mu_0000000004; Object Layer Attributes #2, Unité: m²; Object Layer Attributes #2, Nom_de_macro: Mur; Object Layer Attributes #3, Catégorie de transformation: Nouvelle construction; Object Layer Attributes #3, Métier: Peintures; Object Layer Attributes #3, Id_élt_Allmétré: 0041Mu_0000000005; Object Layer Attributes #3, Unité: m²; Object Layer Attributes #3, Nom_de_macro: Mur
 | RDC | layer 0.07 m | 0042HMu0000000002 | Peintures | 0042Mu_0000000003
 | RDC | layer 0.07 m | 0042HMu0000000009 | Peintures | 0042Mu_0000000010
 | RDC | layer 0.07 m | 0042HMu0000000042 | Peintures | 0042Mu_0000000043
 | RDC | layer 0.07 m | 0042HMu0000000022 | Peintures | 0042Mu_0000000023
 | RDC | layer 0.07 m | 0042HMu0000000062 | Peintures | 0042Mu_0000000063
 | RDC | layer 0.07 m | 0042HMu0000000071 | Peintures | 0042Mu_0000000072
 | RDC | layer 0.07 m | 0042HMu0000000083 | Peintures | 0042Mu_0000000084
 | RDC | layer 0.07 m | 0042HMu0000000032 | Peintures | 0042Mu_0000000033
 | RDC | layer 0.07 m | 0042HMu0000000574 | Peintures | 0042Mu_0000000575
 | RDC | layer 0.07 m | 0042HMu0000000579 | Peintures | 0042Mu_0000000580
 | RDC | Bois & Verre 0.05 m | 0043HMu0000000002 | Menuiserie | 0043Mu_0000000003 | AllplanAttributes - Object Layer Attributes #1, Matériau: Bois & Verre
 | RDC | Bois & Verre 0.05 m | 0043HMu0000000020 | Menuiserie | 0043Mu_0000000021 | AllplanAttributes - Object Layer Attributes #1, Matériau: Bois & Verre
 | RDC | Bois & Verre 0.05 m | 0043HMu0000000031 | Menuiserie | 0043Mu_0000000032 | AllplanAttributes - Object Layer Attributes #1, Matériau: Bois & Verre
 | RDC | Bois & Verre 0.05 m | 0043HMu0000000042 | Menuiserie | 0043Mu_0000000043 | AllplanAttributes - Object Layer Attributes #1, Matériau: Bois & Verre
 | RDC | Bois & Verre 0.05 m | 0043HMu0000000056 | Menuiserie | 0043Mu_0000000057 | AllplanAttributes - Object Layer Attributes #1, Matériau: Bois & Verre
 | RDC | Bois & Verre 0.05 m | 0043HMu0000000068 | Menuiserie | 0043Mu_0000000069 | AllplanAttributes - Object Layer Attributes #1, Matériau: Bois & Verre
 | RDC | Bois & Verre 0.05 m | 0043HMu0000000079 | Menuiserie | 0043Mu_0000000080 | AllplanAttributes - Object Layer Attributes #1, Matériau: Bois & Verre
 | RDC | layer 0.2 m | 0046HMu0000000281 | Maçonnerie | 0046Mu_0000000282
 | RDC | layer 0.2 m | 0046HMu0000000286 | Maçonnerie | 0046Mu_0000000287
 | RDC | layer 0.2 m | 0046HMu0000000297 | Maçonnerie | 0046Mu_0000000298
 | RDC | layer 0.2 m | 0046HMu0000000308 | Maçonnerie | 0046Mu_0000000309
 | RDC | layer 0.2 m | 0046HMu0000000322 | Maçonnerie | 0046Mu_0000000323
 | RDC | layer 0.2 m | 0046HMu0000000334 | Maçonnerie | 0046Mu_0000000335
 | RDC | layer 0.2 m | 0046HMu0000000345 | Maçonnerie | 0046Mu_0000000346
 | RDC | layer 0.2 m | 0046HMu0000000356 | Maçonnerie | 0046Mu_0000000357
 | RDC | layer 0.2 m | 0046HMu0000000371 | Maçonnerie | 0046Mu_0000000372
 | RDC | layer 0.2 m | 0046HMu0000000385 | Maçonnerie | 0046Mu_0000000386
 | R+1 | layer 0.2 m, layer 0.2 m, layer 0.02 m | 0050HMu0000000104 | Systèmes d'isolation thermique | 0050Mu_0000000105 | AllplanAttributes - Object Layer Attributes #2, Catégorie de transformation: Nouvelle construction; Object Layer Attributes #2, Métier: Maçonnerie; Object Layer Attributes #2, Id_élt_Allmétré: 0050Mu_0000000106; Object Layer Attributes #2, Unité: m²; Object Layer Attributes #2, Nom_de_macro: Mur; Object Layer Attributes #3, Catégorie de transformation: Nouvelle construction; Object Layer Attributes #3, Métier: Peintures; Object Layer Attributes #3, Id_élt_Allmétré: 0050Mu_0000000107; Object Layer Attributes #3, Unité: m²; Object Layer Attributes #3, Nom_de_macro: Mur
 | R+1 | layer 0.2 m, layer 0.2 m, layer 0.02 m | 0050HMu0000000020 | Systèmes d'isolation thermique | 0050Mu_0000000021 | AllplanAttributes - Object Layer Attributes #2, Catégorie de transformation: Nouvelle construction; Object Layer Attributes #2, Métier: Maçonnerie; Object Layer Attributes #2, Id_élt_Allmétré: 0050Mu_0000000022; Object Layer Attributes #2, Unité: m²; Object Layer Attributes #2, Nom_de_macro: Mur; Object Layer Attributes #3, Catégorie de transformation: Nouvelle construction; Object Layer Attributes #3, Métier: Peintures; Object Layer Attributes #3, Id_élt_Allmétré: 0050Mu_0000000023; Object Layer Attributes #3, Unité: m²; Object Layer Attributes #3, Nom_de_macro: Mur
 | R+1 | layer 0.2 m, layer 0.2 m, layer 0.02 m | 0050HMu0000000032 | Systèmes d'isolation thermique | 0050Mu_0000000033 | AllplanAttributes - Object Layer Attributes #2, Catégorie de transformation: Nouvelle construction; Object Layer Attributes #2, Métier: Maçonnerie; Object Layer Attributes #2, Id_élt_Allmétré: 0050Mu_0000000034; Object Layer Attributes #2, Unité: m²; Object Layer Attributes #2, Nom_de_macro: Mur; Object Layer Attributes #3, Catégorie de transformation: Nouvelle construction; Object Layer Attributes #3, Métier: Peintures; Object Layer Attributes #3, Id_élt_Allmétré: 0050Mu_0000000035; Object Layer Attributes #3, Unité: m²; Object Layer Attributes #3, Nom_de_macro: Mur
 | R+1 | layer 0.2 m, layer 0.2 m, layer 0.02 m | 0050HMu0000000065 | Systèmes d'isolation thermique | 0050Mu_0000000066 | AllplanAttributes - Object Layer Attributes #2, Catégorie de transformation: Nouvelle construction; Object Layer Attributes #2, Métier: Maçonnerie; Object Layer Attributes #2, Id_élt_Allmétré: 0050Mu_0000000067; Object Layer Attributes #2, Unité: m²; Object Layer Attributes #2, Nom_de_macro: Mur; Object Layer Attributes #3, Catégorie de transformation: Nouvelle construction; Object Layer Attributes #3, Métier: Peintures; Object Layer Attributes #3, Id_élt_Allmétré: 0050Mu_0000000068; Object Layer Attributes #3, Unité: m²; Object Layer Attributes #3, Nom_de_macro: Mur
 | R+1 | layer 0.2 m | 0050HMu0000001328 | Systèmes d'isolation thermique | 0050Mu_0000001329
 | R+1 | layer 0.07 m | 0052HMu0000000002 | Enduits et plâtrages | 0052Mu_0000000003
 | R+1 | layer 0.07 m | 0052HMu0000000007 | Enduits et plâtrages | 0052Mu_0000000008
 | R+1 | layer 0.07 m | 0052HMu0000000018 | Enduits et plâtrages | 0052Mu_0000000019
 | R+1 | layer 0.07 m | 0052HMu0000000037 | Enduits et plâtrages | 0052Mu_0000000038
 | R+1 | layer 0.07 m | 0052HMu0000000047 | Enduits et plâtrages | 0052Mu_0000000048
 | R+1 | layer 0.07 m | 0052HMu0000000030 | Enduits et plâtrages | 0052Mu_0000000031
 | R+1 | Bois & Verre 0.05 m | 0059HMu0000000010 | Menuiserie | 0059Mu_0000000011 | AllplanAttributes - Object Layer Attributes #1, Matériau: Bois & Verre
 | R+1 | Bois & Verre 0.05 m | 0059HMu0000000015 | Menuiserie | 0059Mu_0000000016 | AllplanAttributes - Object Layer Attributes #1, Matériau: Bois & Verre
 | R+1 | Bois & Verre 0.05 m | 0059HMu0000000025 | Menuiserie | 0059Mu_0000000026 | AllplanAttributes - Object Layer Attributes #1, Matériau: Bois & Verre

# IfcWindow: 1 vantail blanc (7)
Type - PredefinedType: WINDOW; PartitioningType: SINGLE_PANEL; ParameterTakesPrecedence: no
Type - IfcWindowLiningProperties - LiningDepth: 0.07 m; LiningThickness: 0.07 m; FirstTransomOffset: 0; SecondTransomOffset: 0; FirstMullionOffset: 0; SecondMullionOffset: 0; LiningOffset: 0 m; LiningToPanelOffsetX: 0 m; LiningToPanelOffsetY: 0 m
AllplanAttributes (1 vantail blanc) - V6: 0; V7: 0; V8: 0; V9: 0; Version: 3.0; Désignation: 1 vantail blanc; Plugin_désignation: MainObject; Plugin_nom_objet: SmartPartCompressed; Prendre en compte la part de vitrage: 100; Version_SMT: 6.0; Unité: Qt; Nom_de_macro: Macro de fenêtre, SmartPart
AllplanQuantities - HeightWindowSillOutside: 0.03; HeightWindowSillInside: 0.03; OffsetOpeningBottom: 0; OffsetOpeningTop: 0; OffsetOpeningLeft: 0; OffsetOpeningRight: 0; DeductionOpeningBottom: 70; DeductionOpeningLeft: 70; DeductionOpeningRight: 70; DeductionOpeningTop: 70
Name | In | OverallHeight (m) | OverallWidth (m) | Id_élt_Allmétré | GlassSurface
1 vantail blanc | RDC | 0.85 | 0.6 | 0040MaU0000003377 | 0.26
1 vantail blanc | RDC | 0.85 | 0.8 | 0040MaU0000003515 | 0.39
1 vantail blanc | RDC | 0.85 | 0.8 | 0040MaU0000003518 | 0.39
1 vantail blanc | RDC | 1.85 | 0.8 | 0040MaU0000003469 | 0.99
1 vantail blanc | RDC | 1.85 | 0.8 | 0040MaU0000003423 | 0.99
1 vantail blanc | R+1 | 1.35 | 0.8 | 0050MaU0000001032 | 0.69
1 vantail blanc | R+1 | 1.35 | 0.8 | 0050MaU0000001273 | 0.69

# IfcWindow: 3 vantaux blanc, monté (4)
Type - PredefinedType: WINDOW; PartitioningType: DOUBLE_PANEL_VERTICAL; ParameterTakesPrecedence: no
Type - IfcWindowLiningProperties - LiningDepth: 0.07 m; LiningThickness: 0.07 m; FirstTransomOffset: 0; SecondTransomOffset: 0; FirstMullionOffset: 0; SecondMullionOffset: 0; LiningOffset: 0 m; LiningToPanelOffsetX: 0 m; LiningToPanelOffsetY: 0 m
OverallWidth: 1.4 m
AllplanAttributes (3 vantaux blanc, monté) - V6: 0; V7: 0; V8: 0; V9: 0; Version: 3.0; Désignation: 3 vantaux blanc, monté; Plugin_désignation: MainObject; Plugin_nom_objet: SmartPartCompressed; Prendre en compte la part de vitrage: 100; Version_SMT: 6.0; Unité: Qt; Nom_de_macro: Macro de fenêtre, SmartPart
AllplanQuantities - HeightWindowSillOutside: 0.03; HeightWindowSillInside: 0.03; OffsetOpeningBottom: 0; OffsetOpeningTop: 0; OffsetOpeningLeft: 0; OffsetOpeningRight: 0; DeductionOpeningBottom: 70; DeductionOpeningLeft: 70; DeductionOpeningRight: 70; DeductionOpeningTop: 70
Name | In | OverallHeight (m) | Id_élt_Allmétré | GlassSurface
3 vantaux blanc, monté | RDC | 1.45 | 0040MaU0000002915 | 1.37375
3 vantaux blanc, monté | RDC | 0.85 | 0040MaU0000003074 | 0.71435
3 vantaux blanc, monté | RDC | 1.45 | 0040MaU0000003156 | 1.37375
3 vantaux blanc, monté | R+1 | 1.45 | 0050MaU0000000982 | 1.37375
